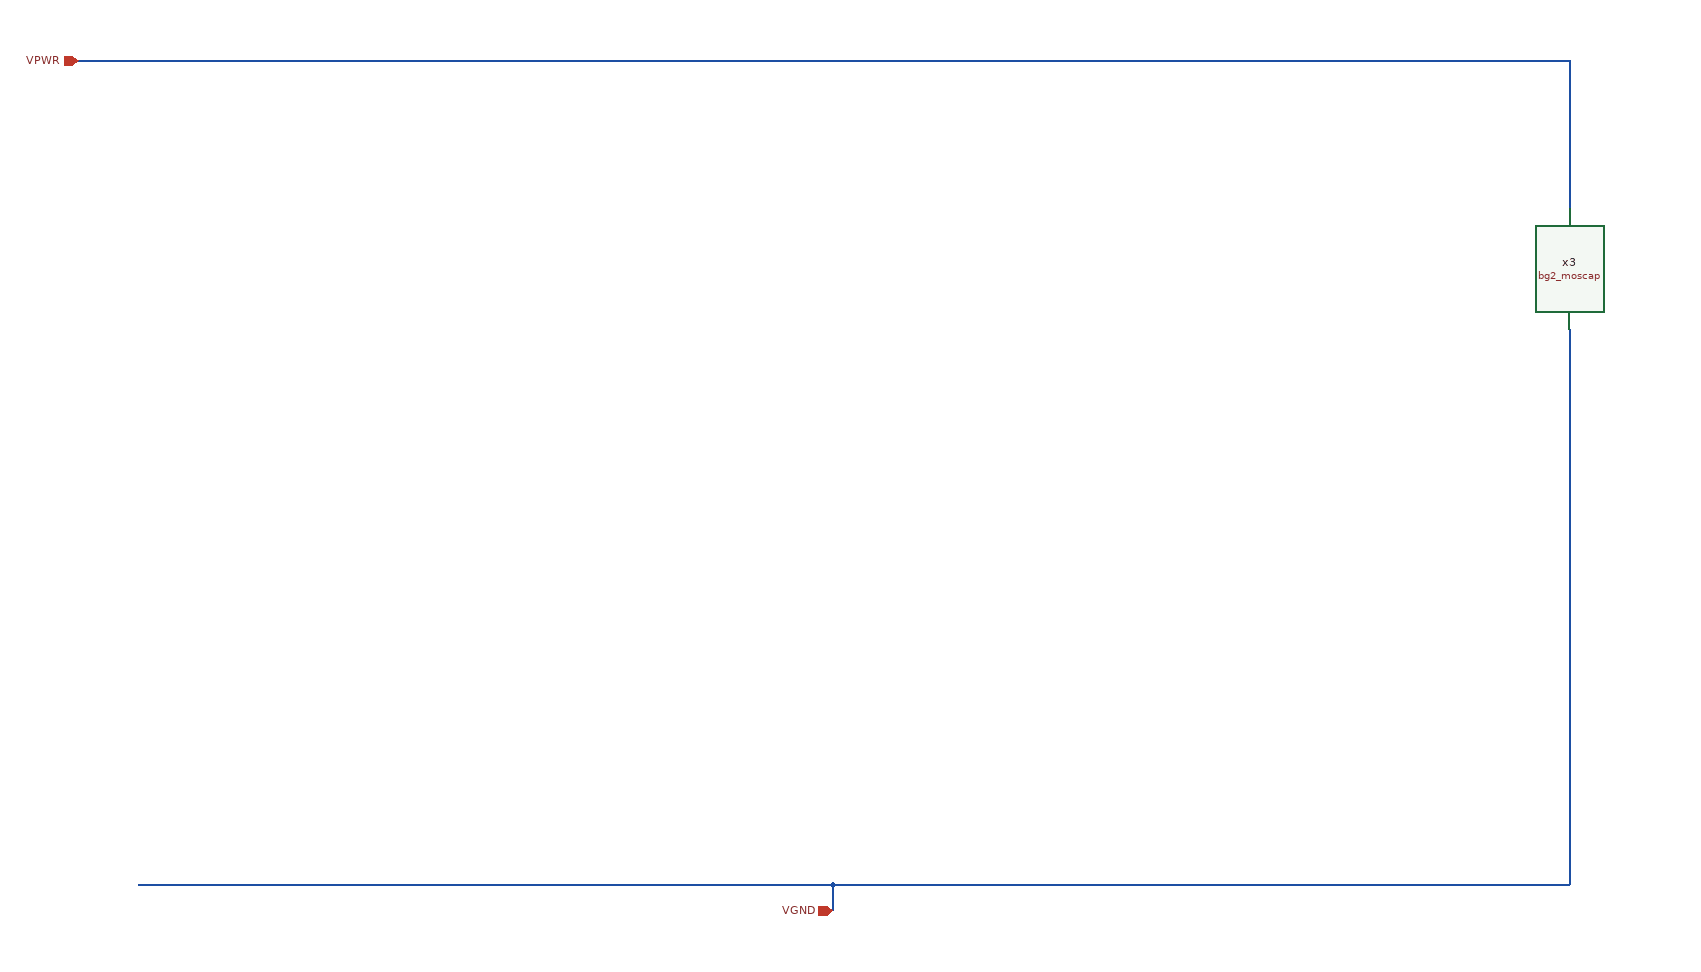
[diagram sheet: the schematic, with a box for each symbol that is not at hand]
v {xschem version=3.4.8RC file_version=1.3}
G {}
K {}
V {}
S {}
F {}
E {}
N 380 -1120 670 -1120 {lab=VPWR}
N 890 -1120 1180 -1120 {lab=VPWR}
N 1180 -1120 1280 -1120 {lab=VPWR}
N 670 -170 820 -170 {lab=VGND}
N 1040 -170 1040 -140 {lab=VGND}
N 1040 -170 1180 -170 {lab=VGND}
N 1450 -170 1590 -170 {lab=VGND}
N 670 -1120 860 -1120 {lab=VPWR}
N 860 -1120 890 -1120 {lab=VPWR}
N 820 -170 1030 -170 {lab=VGND}
N 1030 -170 1040 -170 {lab=VGND}
N 1180 -170 1330 -170 {lab=VGND}
N 1330 -170 1440 -170 {lab=VGND}
N 1440 -170 1450 -170 {lab=VGND}
N 170 -1120 380 -1120 {lab=VPWR}
N 320 -170 530 -170 {lab=VGND}
N 530 -170 670 -170 {lab=VGND}
N 1590 -170 1640 -170 {lab=VGND}
N 1280 -1120 1390 -1120 {lab=VPWR}
N 240 -170 320 -170 {lab=VGND}
N 1640 -170 1890 -170 {lab=VGND}
N 1890 -810 1890 -170 {lab=VGND}
N 1890 -1120 1890 -950 {lab=VPWR}
N 1390 -1120 1890 -1120 {lab=VPWR}
C {ipin.sym} 1040 -140 0 0 {name=p11 lab=VGND}
C {ipin.sym} 170 -1120 0 0 {name=p12 lab=VPWR}
C {bg2_moscap.sym} 1890 -830 0 0 {name=x3}
